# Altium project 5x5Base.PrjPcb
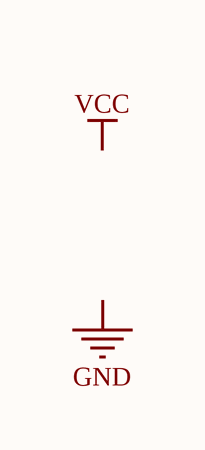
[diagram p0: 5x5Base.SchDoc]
1 sheet, 0 parts. Net scope: global (net labels, ports and power ports of the same name join across sheets).
Board file: 5x5Base.PcbDoc

## Sheet 5x5Base.SchDoc
size A3; SheetNumber: 1; SheetTotal: 1

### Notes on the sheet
- Labels drawn without touching a wire or pin: GND, VCC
